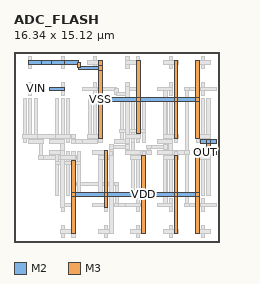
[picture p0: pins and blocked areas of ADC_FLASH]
MACRO ADC_FLASH
  ORIGIN 0 0 ;
  FOREIGN ADC_FLASH 0 0 ;
  SIZE 16.34 BY 15.12 ;
  PIN VSS
    DIRECTION INOUT ;
    USE SIGNAL ;
    PORT 
      LAYER M2 ;
        RECT 1.12 14.14 2.32 14.42 ;
      LAYER M2 ;
        RECT 2.84 14.14 4.04 14.42 ;
      LAYER M3 ;
        RECT 6.74 8.24 7.02 14.44 ;
      LAYER M3 ;
        RECT 9.75 8.66 10.03 14.44 ;
      LAYER M3 ;
        RECT 6.74 11.155 7.02 11.525 ;
      LAYER M2 ;
        RECT 6.88 11.2 9.89 11.48 ;
      LAYER M3 ;
        RECT 9.75 11.155 10.03 11.525 ;
      LAYER M3 ;
        RECT 12.76 8.24 13.04 14.44 ;
      LAYER M3 ;
        RECT 14.48 8.24 14.76 14.44 ;
      LAYER M3 ;
        RECT 12.76 11.155 13.04 11.525 ;
      LAYER M2 ;
        RECT 12.9 11.2 14.62 11.48 ;
      LAYER M3 ;
        RECT 14.48 11.155 14.76 11.525 ;
      LAYER M2 ;
        RECT 2.15 14.14 3.01 14.42 ;
      LAYER M2 ;
        RECT 3.87 14.14 5.16 14.42 ;
      LAYER M3 ;
        RECT 5.02 13.86 5.3 14.28 ;
      LAYER M2 ;
        RECT 5.16 13.72 6.88 14 ;
      LAYER M3 ;
        RECT 6.74 13.675 7.02 14.045 ;
      LAYER M2 ;
        RECT 9.89 11.2 12.9 11.48 ;
    END
  END VSS
  PIN VDD
    DIRECTION INOUT ;
    USE SIGNAL ;
    PORT 
      LAYER M3 ;
        RECT 4.59 0.68 4.87 6.46 ;
      LAYER M3 ;
        RECT 7.17 2.78 7.45 7.3 ;
      LAYER M3 ;
        RECT 10.18 0.68 10.46 6.88 ;
      LAYER M3 ;
        RECT 12.76 0.68 13.04 6.88 ;
      LAYER M3 ;
        RECT 14.48 0.68 14.76 6.88 ;
      LAYER M3 ;
        RECT 12.76 3.595 13.04 3.965 ;
      LAYER M2 ;
        RECT 12.9 3.64 14.62 3.92 ;
      LAYER M3 ;
        RECT 14.48 3.595 14.76 3.965 ;
      LAYER M3 ;
        RECT 4.59 3.595 4.87 3.965 ;
      LAYER M2 ;
        RECT 4.73 3.64 7.31 3.92 ;
      LAYER M3 ;
        RECT 7.17 3.595 7.45 3.965 ;
      LAYER M2 ;
        RECT 7.31 3.64 10.32 3.92 ;
      LAYER M3 ;
        RECT 10.18 3.595 10.46 3.965 ;
      LAYER M2 ;
        RECT 10.32 3.64 12.9 3.92 ;
    END
  END VDD
  PIN OUT
    DIRECTION INOUT ;
    USE SIGNAL ;
    PORT 
      LAYER M2 ;
        RECT 14.88 7 16.08 7.28 ;
      LAYER M2 ;
        RECT 14.88 7.84 16.08 8.12 ;
      LAYER M2 ;
        RECT 15.32 7 15.64 7.28 ;
      LAYER M3 ;
        RECT 15.34 7.14 15.62 7.98 ;
      LAYER M2 ;
        RECT 15.32 7.84 15.64 8.12 ;
    END
  END OUT
  PIN VIN
    DIRECTION INOUT ;
    USE SIGNAL ;
    PORT 
      LAYER M2 ;
        RECT 1.12 12.04 2.32 12.32 ;
    END
  END VIN
  PIN VREF
    DIRECTION INOUT ;
    USE SIGNAL ;
    PORT 
      LAYER M2 ;
        RECT 2.84 12.04 4.04 12.32 ;
    END
  END VREF
  OBS 
  LAYER M2 ;
        RECT 11.44 2.8 12.64 3.08 ;
  LAYER M2 ;
        RECT 11.44 12.04 12.64 12.32 ;
  LAYER M2 ;
        RECT 11.88 2.8 12.2 3.08 ;
  LAYER M3 ;
        RECT 11.9 2.94 12.18 12.18 ;
  LAYER M2 ;
        RECT 11.88 12.04 12.2 12.32 ;
  LAYER M2 ;
        RECT 8.86 7 10.06 7.28 ;
  LAYER M2 ;
        RECT 8.86 8.26 10.06 8.54 ;
  LAYER M3 ;
        RECT 11.9 7.375 12.18 7.745 ;
  LAYER M2 ;
        RECT 10.75 7.42 12.04 7.7 ;
  LAYER M1 ;
        RECT 10.625 7.14 10.875 7.56 ;
  LAYER M2 ;
        RECT 9.89 7 10.75 7.28 ;
  LAYER M2 ;
        RECT 9.3 7 9.62 7.28 ;
  LAYER M3 ;
        RECT 9.32 7.14 9.6 8.4 ;
  LAYER M2 ;
        RECT 9.3 8.26 9.62 8.54 ;
  LAYER M1 ;
        RECT 10.625 7.055 10.875 7.225 ;
  LAYER M2 ;
        RECT 10.58 7 10.92 7.28 ;
  LAYER M1 ;
        RECT 10.625 7.475 10.875 7.645 ;
  LAYER M2 ;
        RECT 10.58 7.42 10.92 7.7 ;
  LAYER M2 ;
        RECT 11.88 7.42 12.2 7.7 ;
  LAYER M3 ;
        RECT 11.9 7.4 12.18 7.72 ;
  LAYER M1 ;
        RECT 10.625 7.055 10.875 7.225 ;
  LAYER M2 ;
        RECT 10.58 7 10.92 7.28 ;
  LAYER M1 ;
        RECT 10.625 7.475 10.875 7.645 ;
  LAYER M2 ;
        RECT 10.58 7.42 10.92 7.7 ;
  LAYER M2 ;
        RECT 11.88 7.42 12.2 7.7 ;
  LAYER M3 ;
        RECT 11.9 7.4 12.18 7.72 ;
  LAYER M1 ;
        RECT 10.625 7.055 10.875 7.225 ;
  LAYER M2 ;
        RECT 10.58 7 10.92 7.28 ;
  LAYER M1 ;
        RECT 10.625 7.475 10.875 7.645 ;
  LAYER M2 ;
        RECT 10.58 7.42 10.92 7.7 ;
  LAYER M2 ;
        RECT 9.3 7 9.62 7.28 ;
  LAYER M3 ;
        RECT 9.32 6.98 9.6 7.3 ;
  LAYER M2 ;
        RECT 9.3 8.26 9.62 8.54 ;
  LAYER M3 ;
        RECT 9.32 8.24 9.6 8.56 ;
  LAYER M2 ;
        RECT 11.88 7.42 12.2 7.7 ;
  LAYER M3 ;
        RECT 11.9 7.4 12.18 7.72 ;
  LAYER M1 ;
        RECT 10.625 7.055 10.875 7.225 ;
  LAYER M2 ;
        RECT 10.58 7 10.92 7.28 ;
  LAYER M1 ;
        RECT 10.625 7.475 10.875 7.645 ;
  LAYER M2 ;
        RECT 10.58 7.42 10.92 7.7 ;
  LAYER M2 ;
        RECT 9.3 7 9.62 7.28 ;
  LAYER M3 ;
        RECT 9.32 6.98 9.6 7.3 ;
  LAYER M2 ;
        RECT 9.3 8.26 9.62 8.54 ;
  LAYER M3 ;
        RECT 9.32 8.24 9.6 8.56 ;
  LAYER M2 ;
        RECT 11.88 7.42 12.2 7.7 ;
  LAYER M3 ;
        RECT 11.9 7.4 12.18 7.72 ;
  LAYER M3 ;
        RECT 7.6 0.68 7.88 6.88 ;
  LAYER M2 ;
        RECT 5.42 12.04 6.62 12.32 ;
  LAYER M3 ;
        RECT 8.89 7.82 9.17 12.34 ;
  LAYER M2 ;
        RECT 6.45 12.04 8.17 12.32 ;
  LAYER M3 ;
        RECT 8.03 11.76 8.31 12.18 ;
  LAYER M2 ;
        RECT 8.17 11.62 9.03 11.9 ;
  LAYER M3 ;
        RECT 8.89 11.575 9.17 11.945 ;
  LAYER M3 ;
        RECT 7.6 6.72 7.88 7.56 ;
  LAYER M2 ;
        RECT 7.74 7.42 9.03 7.7 ;
  LAYER M3 ;
        RECT 8.89 7.56 9.17 7.98 ;
  LAYER M2 ;
        RECT 7.58 7.42 7.9 7.7 ;
  LAYER M3 ;
        RECT 7.6 7.4 7.88 7.72 ;
  LAYER M2 ;
        RECT 8.87 7.42 9.19 7.7 ;
  LAYER M3 ;
        RECT 8.89 7.4 9.17 7.72 ;
  LAYER M2 ;
        RECT 7.58 7.42 7.9 7.7 ;
  LAYER M3 ;
        RECT 7.6 7.4 7.88 7.72 ;
  LAYER M2 ;
        RECT 8.87 7.42 9.19 7.7 ;
  LAYER M3 ;
        RECT 8.89 7.4 9.17 7.72 ;
  LAYER M2 ;
        RECT 0.69 8.26 1.89 8.54 ;
  LAYER M2 ;
        RECT 3.27 8.26 4.47 8.54 ;
  LAYER M2 ;
        RECT 5.42 7.84 6.62 8.12 ;
  LAYER M2 ;
        RECT 1.72 8.26 3.44 8.54 ;
  LAYER M2 ;
        RECT 4.3 8.26 4.73 8.54 ;
  LAYER M1 ;
        RECT 4.605 7.98 4.855 8.4 ;
  LAYER M2 ;
        RECT 4.73 7.84 5.59 8.12 ;
  LAYER M1 ;
        RECT 4.605 7.895 4.855 8.065 ;
  LAYER M2 ;
        RECT 4.56 7.84 4.9 8.12 ;
  LAYER M1 ;
        RECT 4.605 8.315 4.855 8.485 ;
  LAYER M2 ;
        RECT 4.56 8.26 4.9 8.54 ;
  LAYER M1 ;
        RECT 4.605 7.895 4.855 8.065 ;
  LAYER M2 ;
        RECT 4.56 7.84 4.9 8.12 ;
  LAYER M1 ;
        RECT 4.605 8.315 4.855 8.485 ;
  LAYER M2 ;
        RECT 4.56 8.26 4.9 8.54 ;
  LAYER M3 ;
        RECT 3.73 2.78 4.01 7.3 ;
  LAYER M2 ;
        RECT 2.84 7.84 4.04 8.12 ;
  LAYER M3 ;
        RECT 3.73 7.14 4.01 7.98 ;
  LAYER M2 ;
        RECT 3.71 7.84 4.03 8.12 ;
  LAYER M2 ;
        RECT 3.71 7.84 4.03 8.12 ;
  LAYER M3 ;
        RECT 3.73 7.82 4.01 8.14 ;
  LAYER M2 ;
        RECT 3.71 7.84 4.03 8.12 ;
  LAYER M3 ;
        RECT 3.73 7.82 4.01 8.14 ;
  LAYER M2 ;
        RECT 1.12 7.84 2.32 8.12 ;
  LAYER M2 ;
        RECT 3.7 6.58 4.9 6.86 ;
  LAYER M2 ;
        RECT 8.86 2.8 10.06 3.08 ;
  LAYER M2 ;
        RECT 1.99 7.84 2.31 8.12 ;
  LAYER M1 ;
        RECT 2.025 6.72 2.275 7.98 ;
  LAYER M2 ;
        RECT 2.15 6.58 3.87 6.86 ;
  LAYER M2 ;
        RECT 4.73 6.58 5.16 6.86 ;
  LAYER M3 ;
        RECT 5.02 4.62 5.3 6.72 ;
  LAYER M2 ;
        RECT 5.16 4.48 8.17 4.76 ;
  LAYER M1 ;
        RECT 8.045 2.94 8.295 4.62 ;
  LAYER M2 ;
        RECT 8.17 2.8 9.03 3.08 ;
  LAYER M1 ;
        RECT 2.025 6.635 2.275 6.805 ;
  LAYER M2 ;
        RECT 1.98 6.58 2.32 6.86 ;
  LAYER M1 ;
        RECT 2.025 7.895 2.275 8.065 ;
  LAYER M2 ;
        RECT 1.98 7.84 2.32 8.12 ;
  LAYER M1 ;
        RECT 2.025 6.635 2.275 6.805 ;
  LAYER M2 ;
        RECT 1.98 6.58 2.32 6.86 ;
  LAYER M1 ;
        RECT 2.025 7.895 2.275 8.065 ;
  LAYER M2 ;
        RECT 1.98 7.84 2.32 8.12 ;
  LAYER M1 ;
        RECT 2.025 6.635 2.275 6.805 ;
  LAYER M2 ;
        RECT 1.98 6.58 2.32 6.86 ;
  LAYER M1 ;
        RECT 2.025 7.895 2.275 8.065 ;
  LAYER M2 ;
        RECT 1.98 7.84 2.32 8.12 ;
  LAYER M1 ;
        RECT 8.045 2.855 8.295 3.025 ;
  LAYER M2 ;
        RECT 8 2.8 8.34 3.08 ;
  LAYER M1 ;
        RECT 8.045 4.535 8.295 4.705 ;
  LAYER M2 ;
        RECT 8 4.48 8.34 4.76 ;
  LAYER M2 ;
        RECT 5 4.48 5.32 4.76 ;
  LAYER M3 ;
        RECT 5.02 4.46 5.3 4.78 ;
  LAYER M2 ;
        RECT 5 6.58 5.32 6.86 ;
  LAYER M3 ;
        RECT 5.02 6.56 5.3 6.88 ;
  LAYER M1 ;
        RECT 2.025 6.635 2.275 6.805 ;
  LAYER M2 ;
        RECT 1.98 6.58 2.32 6.86 ;
  LAYER M1 ;
        RECT 2.025 7.895 2.275 8.065 ;
  LAYER M2 ;
        RECT 1.98 7.84 2.32 8.12 ;
  LAYER M1 ;
        RECT 8.045 2.855 8.295 3.025 ;
  LAYER M2 ;
        RECT 8 2.8 8.34 3.08 ;
  LAYER M1 ;
        RECT 8.045 4.535 8.295 4.705 ;
  LAYER M2 ;
        RECT 8 4.48 8.34 4.76 ;
  LAYER M2 ;
        RECT 5 4.48 5.32 4.76 ;
  LAYER M3 ;
        RECT 5.02 4.46 5.3 4.78 ;
  LAYER M2 ;
        RECT 5 6.58 5.32 6.86 ;
  LAYER M3 ;
        RECT 5.02 6.56 5.3 6.88 ;
  LAYER M2 ;
        RECT 14.88 2.8 16.08 3.08 ;
  LAYER M2 ;
        RECT 11.44 7 12.64 7.28 ;
  LAYER M2 ;
        RECT 11.44 7.84 12.64 8.12 ;
  LAYER M2 ;
        RECT 14.88 12.04 16.08 12.32 ;
  LAYER M2 ;
        RECT 13.76 2.8 15.05 3.08 ;
  LAYER M1 ;
        RECT 13.635 2.94 13.885 7.14 ;
  LAYER M2 ;
        RECT 12.47 7 13.76 7.28 ;
  LAYER M2 ;
        RECT 12.31 7 12.63 7.28 ;
  LAYER M3 ;
        RECT 12.33 7.14 12.61 7.98 ;
  LAYER M2 ;
        RECT 12.31 7.84 12.63 8.12 ;
  LAYER M1 ;
        RECT 13.635 7.14 13.885 12.18 ;
  LAYER M2 ;
        RECT 13.76 12.04 15.05 12.32 ;
  LAYER M1 ;
        RECT 13.635 2.855 13.885 3.025 ;
  LAYER M2 ;
        RECT 13.59 2.8 13.93 3.08 ;
  LAYER M1 ;
        RECT 13.635 7.055 13.885 7.225 ;
  LAYER M2 ;
        RECT 13.59 7 13.93 7.28 ;
  LAYER M1 ;
        RECT 13.635 2.855 13.885 3.025 ;
  LAYER M2 ;
        RECT 13.59 2.8 13.93 3.08 ;
  LAYER M1 ;
        RECT 13.635 7.055 13.885 7.225 ;
  LAYER M2 ;
        RECT 13.59 7 13.93 7.28 ;
  LAYER M1 ;
        RECT 13.635 2.855 13.885 3.025 ;
  LAYER M2 ;
        RECT 13.59 2.8 13.93 3.08 ;
  LAYER M1 ;
        RECT 13.635 7.055 13.885 7.225 ;
  LAYER M2 ;
        RECT 13.59 7 13.93 7.28 ;
  LAYER M2 ;
        RECT 12.31 7 12.63 7.28 ;
  LAYER M3 ;
        RECT 12.33 6.98 12.61 7.3 ;
  LAYER M2 ;
        RECT 12.31 7.84 12.63 8.12 ;
  LAYER M3 ;
        RECT 12.33 7.82 12.61 8.14 ;
  LAYER M1 ;
        RECT 13.635 2.855 13.885 3.025 ;
  LAYER M2 ;
        RECT 13.59 2.8 13.93 3.08 ;
  LAYER M1 ;
        RECT 13.635 7.055 13.885 7.225 ;
  LAYER M2 ;
        RECT 13.59 7 13.93 7.28 ;
  LAYER M2 ;
        RECT 12.31 7 12.63 7.28 ;
  LAYER M3 ;
        RECT 12.33 6.98 12.61 7.3 ;
  LAYER M2 ;
        RECT 12.31 7.84 12.63 8.12 ;
  LAYER M3 ;
        RECT 12.33 7.82 12.61 8.14 ;
  LAYER M1 ;
        RECT 13.635 2.855 13.885 3.025 ;
  LAYER M2 ;
        RECT 13.59 2.8 13.93 3.08 ;
  LAYER M1 ;
        RECT 13.635 7.055 13.885 7.225 ;
  LAYER M2 ;
        RECT 13.59 7 13.93 7.28 ;
  LAYER M1 ;
        RECT 13.635 12.095 13.885 12.265 ;
  LAYER M2 ;
        RECT 13.59 12.04 13.93 12.32 ;
  LAYER M2 ;
        RECT 12.31 7 12.63 7.28 ;
  LAYER M3 ;
        RECT 12.33 6.98 12.61 7.3 ;
  LAYER M2 ;
        RECT 12.31 7.84 12.63 8.12 ;
  LAYER M3 ;
        RECT 12.33 7.82 12.61 8.14 ;
  LAYER M1 ;
        RECT 13.635 2.855 13.885 3.025 ;
  LAYER M2 ;
        RECT 13.59 2.8 13.93 3.08 ;
  LAYER M1 ;
        RECT 13.635 7.055 13.885 7.225 ;
  LAYER M2 ;
        RECT 13.59 7 13.93 7.28 ;
  LAYER M1 ;
        RECT 13.635 12.095 13.885 12.265 ;
  LAYER M2 ;
        RECT 13.59 12.04 13.93 12.32 ;
  LAYER M2 ;
        RECT 12.31 7 12.63 7.28 ;
  LAYER M3 ;
        RECT 12.33 6.98 12.61 7.3 ;
  LAYER M2 ;
        RECT 12.31 7.84 12.63 8.12 ;
  LAYER M3 ;
        RECT 12.33 7.82 12.61 8.14 ;
  LAYER M1 ;
        RECT 12.345 7.895 12.595 11.425 ;
  LAYER M1 ;
        RECT 12.345 11.675 12.595 12.685 ;
  LAYER M1 ;
        RECT 12.345 13.775 12.595 14.785 ;
  LAYER M1 ;
        RECT 11.915 7.895 12.165 11.425 ;
  LAYER M1 ;
        RECT 12.775 7.895 13.025 11.425 ;
  LAYER M2 ;
        RECT 11.87 8.26 13.07 8.54 ;
  LAYER M2 ;
        RECT 11.87 14.14 13.07 14.42 ;
  LAYER M2 ;
        RECT 11.44 7.84 12.64 8.12 ;
  LAYER M2 ;
        RECT 11.44 12.04 12.64 12.32 ;
  LAYER M3 ;
        RECT 12.76 8.24 13.04 14.44 ;
  LAYER M1 ;
        RECT 14.925 7.895 15.175 11.425 ;
  LAYER M1 ;
        RECT 14.925 11.675 15.175 12.685 ;
  LAYER M1 ;
        RECT 14.925 13.775 15.175 14.785 ;
  LAYER M1 ;
        RECT 15.355 7.895 15.605 11.425 ;
  LAYER M1 ;
        RECT 14.495 7.895 14.745 11.425 ;
  LAYER M2 ;
        RECT 14.45 8.26 15.65 8.54 ;
  LAYER M2 ;
        RECT 14.45 14.14 15.65 14.42 ;
  LAYER M2 ;
        RECT 14.88 7.84 16.08 8.12 ;
  LAYER M2 ;
        RECT 14.88 12.04 16.08 12.32 ;
  LAYER M3 ;
        RECT 14.48 8.24 14.76 14.44 ;
  LAYER M1 ;
        RECT 12.345 3.695 12.595 7.225 ;
  LAYER M1 ;
        RECT 12.345 2.435 12.595 3.445 ;
  LAYER M1 ;
        RECT 12.345 0.335 12.595 1.345 ;
  LAYER M1 ;
        RECT 11.915 3.695 12.165 7.225 ;
  LAYER M1 ;
        RECT 12.775 3.695 13.025 7.225 ;
  LAYER M2 ;
        RECT 11.87 6.58 13.07 6.86 ;
  LAYER M2 ;
        RECT 11.87 0.7 13.07 0.98 ;
  LAYER M2 ;
        RECT 11.44 7 12.64 7.28 ;
  LAYER M2 ;
        RECT 11.44 2.8 12.64 3.08 ;
  LAYER M3 ;
        RECT 12.76 0.68 13.04 6.88 ;
  LAYER M1 ;
        RECT 14.925 3.695 15.175 7.225 ;
  LAYER M1 ;
        RECT 14.925 2.435 15.175 3.445 ;
  LAYER M1 ;
        RECT 14.925 0.335 15.175 1.345 ;
  LAYER M1 ;
        RECT 15.355 3.695 15.605 7.225 ;
  LAYER M1 ;
        RECT 14.495 3.695 14.745 7.225 ;
  LAYER M2 ;
        RECT 14.45 6.58 15.65 6.86 ;
  LAYER M2 ;
        RECT 14.45 0.7 15.65 0.98 ;
  LAYER M2 ;
        RECT 14.88 7 16.08 7.28 ;
  LAYER M2 ;
        RECT 14.88 2.8 16.08 3.08 ;
  LAYER M3 ;
        RECT 14.48 0.68 14.76 6.88 ;
  LAYER M1 ;
        RECT 8.905 7.895 9.155 11.425 ;
  LAYER M1 ;
        RECT 8.905 11.675 9.155 12.685 ;
  LAYER M1 ;
        RECT 8.905 13.775 9.155 14.785 ;
  LAYER M1 ;
        RECT 8.475 7.895 8.725 11.425 ;
  LAYER M1 ;
        RECT 9.335 7.895 9.585 11.425 ;
  LAYER M1 ;
        RECT 9.765 7.895 10.015 11.425 ;
  LAYER M1 ;
        RECT 9.765 11.675 10.015 12.685 ;
  LAYER M1 ;
        RECT 9.765 13.775 10.015 14.785 ;
  LAYER M1 ;
        RECT 10.195 7.895 10.445 11.425 ;
  LAYER M2 ;
        RECT 8 7.84 9.2 8.12 ;
  LAYER M2 ;
        RECT 8.86 12.04 10.06 12.32 ;
  LAYER M2 ;
        RECT 8.43 8.68 10.49 8.96 ;
  LAYER M2 ;
        RECT 8.86 14.14 10.06 14.42 ;
  LAYER M3 ;
        RECT 8.89 7.82 9.17 12.34 ;
  LAYER M2 ;
        RECT 8.86 8.26 10.06 8.54 ;
  LAYER M3 ;
        RECT 9.75 8.66 10.03 14.44 ;
  LAYER M1 ;
        RECT 6.325 7.895 6.575 11.425 ;
  LAYER M1 ;
        RECT 6.325 11.675 6.575 12.685 ;
  LAYER M1 ;
        RECT 6.325 13.775 6.575 14.785 ;
  LAYER M1 ;
        RECT 5.895 7.895 6.145 11.425 ;
  LAYER M1 ;
        RECT 6.755 7.895 7.005 11.425 ;
  LAYER M2 ;
        RECT 5.85 8.26 7.05 8.54 ;
  LAYER M2 ;
        RECT 5.85 14.14 7.05 14.42 ;
  LAYER M2 ;
        RECT 5.42 7.84 6.62 8.12 ;
  LAYER M2 ;
        RECT 5.42 12.04 6.62 12.32 ;
  LAYER M3 ;
        RECT 6.74 8.24 7.02 14.44 ;
  LAYER M1 ;
        RECT 3.745 3.695 3.995 7.225 ;
  LAYER M1 ;
        RECT 3.745 2.435 3.995 3.445 ;
  LAYER M1 ;
        RECT 3.745 0.335 3.995 1.345 ;
  LAYER M1 ;
        RECT 3.315 3.695 3.565 7.225 ;
  LAYER M1 ;
        RECT 4.175 3.695 4.425 7.225 ;
  LAYER M1 ;
        RECT 4.605 3.695 4.855 7.225 ;
  LAYER M1 ;
        RECT 4.605 2.435 4.855 3.445 ;
  LAYER M1 ;
        RECT 4.605 0.335 4.855 1.345 ;
  LAYER M1 ;
        RECT 5.035 3.695 5.285 7.225 ;
  LAYER M2 ;
        RECT 2.84 7 4.04 7.28 ;
  LAYER M2 ;
        RECT 3.7 2.8 4.9 3.08 ;
  LAYER M2 ;
        RECT 3.27 6.16 5.33 6.44 ;
  LAYER M2 ;
        RECT 3.7 0.7 4.9 0.98 ;
  LAYER M3 ;
        RECT 3.73 2.78 4.01 7.3 ;
  LAYER M2 ;
        RECT 3.7 6.58 4.9 6.86 ;
  LAYER M3 ;
        RECT 4.59 0.68 4.87 6.46 ;
  LAYER M1 ;
        RECT 7.185 3.695 7.435 7.225 ;
  LAYER M1 ;
        RECT 7.185 2.435 7.435 3.445 ;
  LAYER M1 ;
        RECT 7.185 0.335 7.435 1.345 ;
  LAYER M1 ;
        RECT 6.755 3.695 7.005 7.225 ;
  LAYER M1 ;
        RECT 7.615 3.695 7.865 7.225 ;
  LAYER M2 ;
        RECT 6.28 7 7.48 7.28 ;
  LAYER M2 ;
        RECT 6.28 2.8 7.48 3.08 ;
  LAYER M2 ;
        RECT 6.71 6.58 7.91 6.86 ;
  LAYER M2 ;
        RECT 6.71 0.7 7.91 0.98 ;
  LAYER M3 ;
        RECT 7.17 2.78 7.45 7.3 ;
  LAYER M3 ;
        RECT 7.6 0.68 7.88 6.88 ;
  LAYER M1 ;
        RECT 9.765 3.695 10.015 7.225 ;
  LAYER M1 ;
        RECT 9.765 2.435 10.015 3.445 ;
  LAYER M1 ;
        RECT 9.765 0.335 10.015 1.345 ;
  LAYER M1 ;
        RECT 9.335 3.695 9.585 7.225 ;
  LAYER M1 ;
        RECT 10.195 3.695 10.445 7.225 ;
  LAYER M2 ;
        RECT 9.29 6.58 10.49 6.86 ;
  LAYER M2 ;
        RECT 9.29 0.7 10.49 0.98 ;
  LAYER M2 ;
        RECT 8.86 7 10.06 7.28 ;
  LAYER M2 ;
        RECT 8.86 2.8 10.06 3.08 ;
  LAYER M3 ;
        RECT 10.18 0.68 10.46 6.88 ;
  LAYER M1 ;
        RECT 1.165 7.895 1.415 11.425 ;
  LAYER M1 ;
        RECT 1.165 11.675 1.415 12.685 ;
  LAYER M1 ;
        RECT 1.165 13.775 1.415 14.785 ;
  LAYER M1 ;
        RECT 1.595 7.895 1.845 11.425 ;
  LAYER M1 ;
        RECT 0.735 7.895 0.985 11.425 ;
  LAYER M2 ;
        RECT 1.12 14.14 2.32 14.42 ;
  LAYER M2 ;
        RECT 1.12 7.84 2.32 8.12 ;
  LAYER M2 ;
        RECT 1.12 12.04 2.32 12.32 ;
  LAYER M2 ;
        RECT 0.69 8.26 1.89 8.54 ;
  LAYER M1 ;
        RECT 3.745 7.895 3.995 11.425 ;
  LAYER M1 ;
        RECT 3.745 11.675 3.995 12.685 ;
  LAYER M1 ;
        RECT 3.745 13.775 3.995 14.785 ;
  LAYER M1 ;
        RECT 3.315 7.895 3.565 11.425 ;
  LAYER M1 ;
        RECT 4.175 7.895 4.425 11.425 ;
  LAYER M2 ;
        RECT 2.84 14.14 4.04 14.42 ;
  LAYER M2 ;
        RECT 2.84 7.84 4.04 8.12 ;
  LAYER M2 ;
        RECT 2.84 12.04 4.04 12.32 ;
  LAYER M2 ;
        RECT 3.27 8.26 4.47 8.54 ;
  END 
END ADC_FLASH
